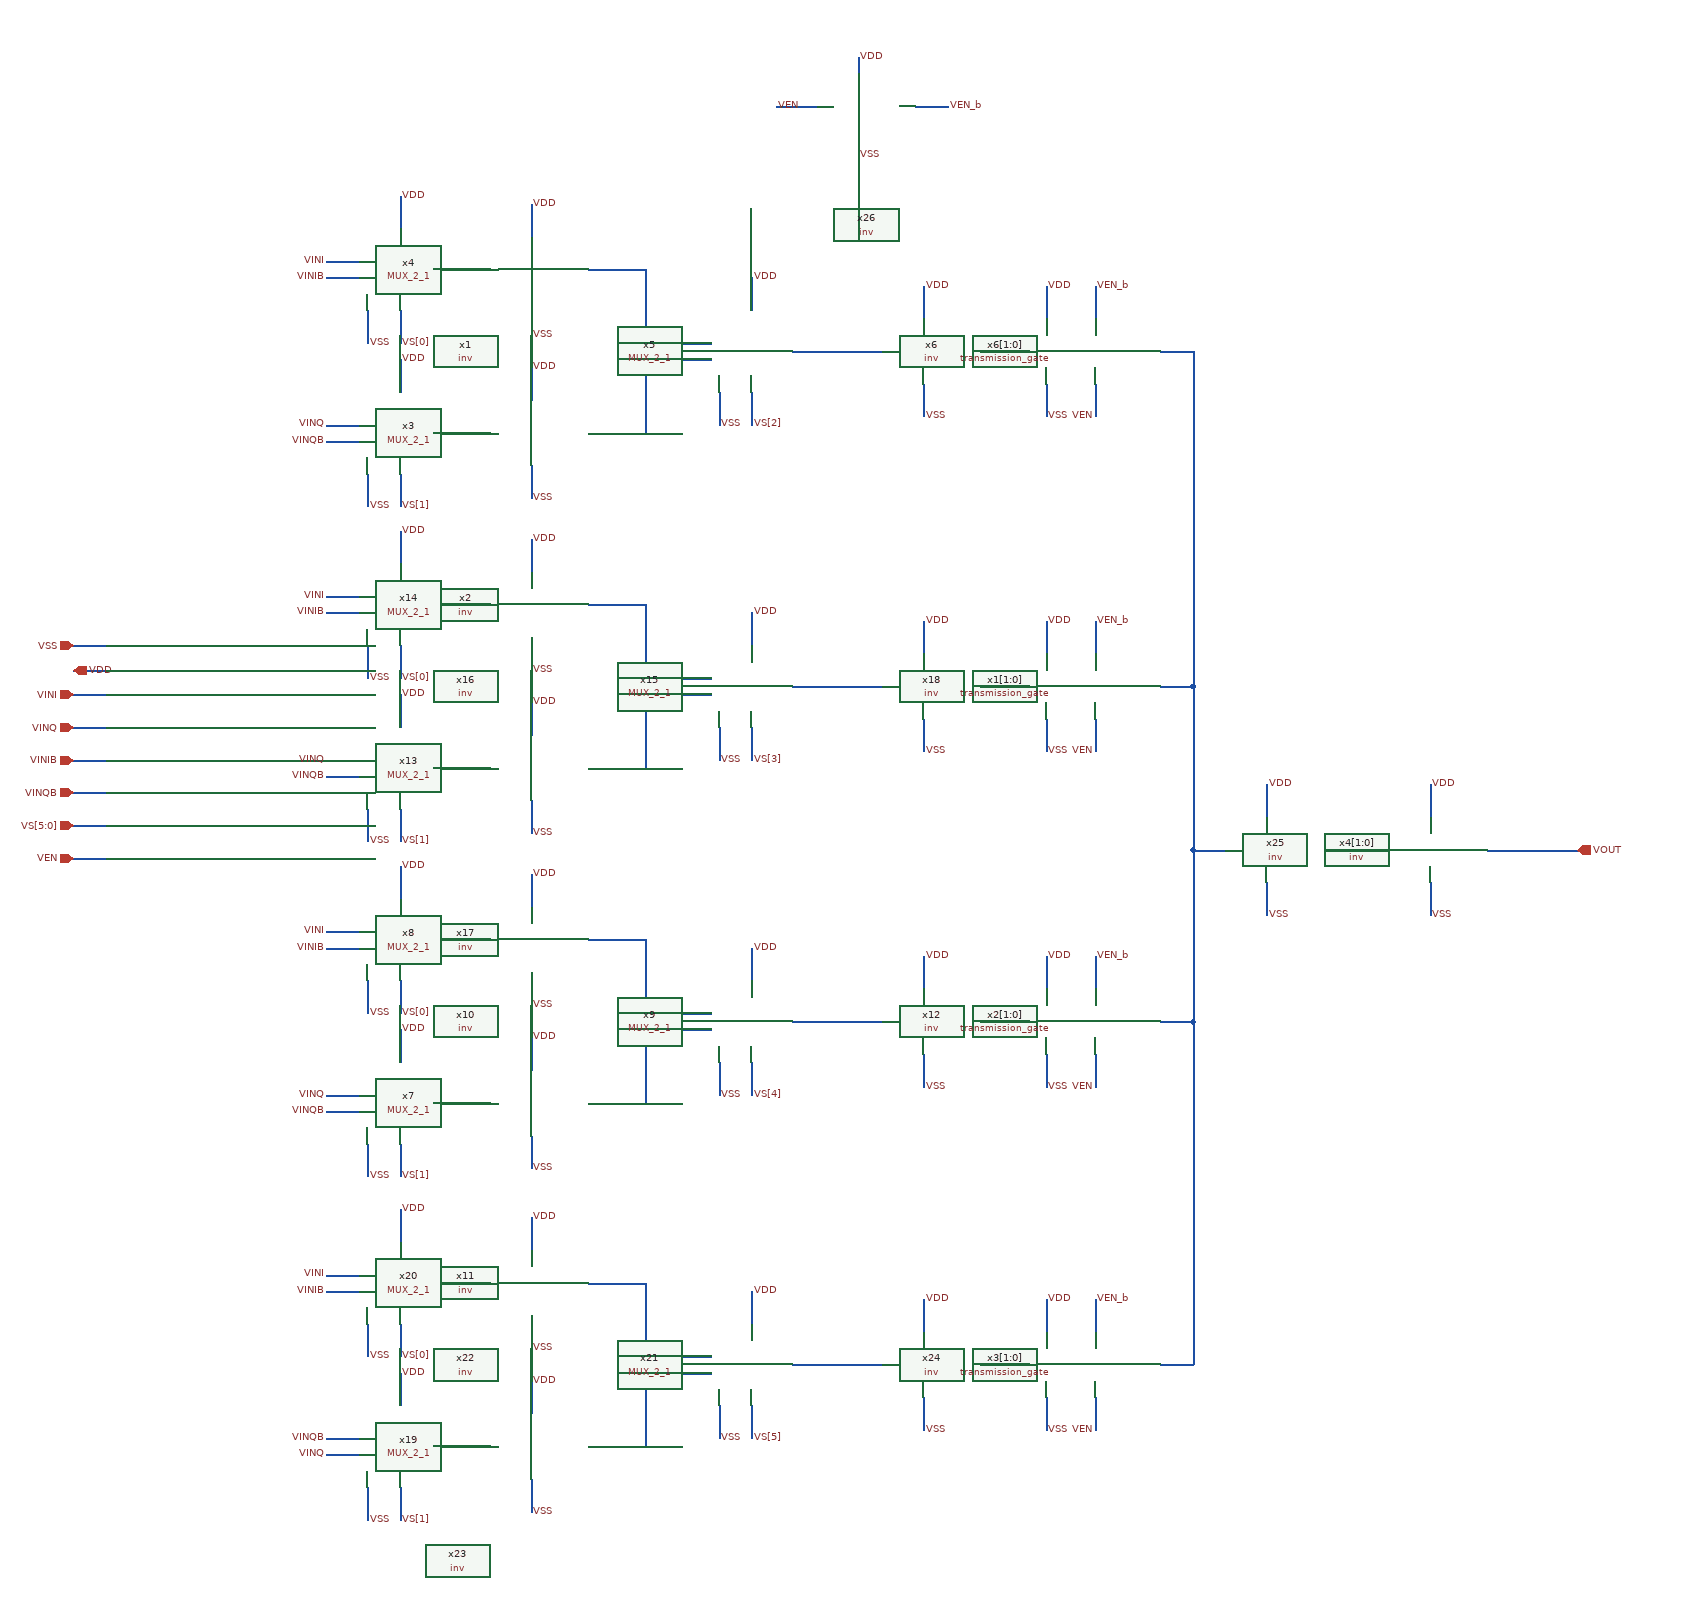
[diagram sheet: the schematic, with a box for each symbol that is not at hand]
v {xschem version=3.4.8RC file_version=1.3}
G {}
K {}
V {}
S {}
F {}
E {}
N -920 -490 -880 -490 {lab=VINI}
N -920 -470 -880 -470 {lab=VINIB}
N -920 -290 -880 -290 {lab=VINQ}
N -920 -270 -880 -270 {lab=VINQB}
N -830 -370 -830 -330 {lab=VDD}
N -870 -430 -870 -390 {lab=VSS}
N -870 -230 -870 -190 {lab=VSS}
N -830 -570 -830 -530 {lab=VDD}
N -830 -430 -830 -390 {lab=VS[0]}
N -830 -230 -830 -190 {lab=VS[1]}
N -440 -330 -440 -290 {lab=VSS}
N -400 -470 -400 -430 {lab=VDD}
N -400 -330 -400 -290 {lab=VS[2]}
N -780 -480 -720 -480 {lab=#net1}
N -780 -280 -720 -280 {lab=#net2}
N -350 -380 -240 -380 {lab=#net3}
N -530 -390 -450 -390 {lab=#net4}
N -530 -370 -450 -370 {lab=#net5}
N -530 -480 -530 -390 {lab=#net4}
N -600 -480 -530 -480 {lab=#net4}
N -530 -370 -530 -280 {lab=#net5}
N -600 -280 -530 -280 {lab=#net5}
N -670 -560 -670 -520 {lab=VDD}
N -190 -460 -190 -420 {lab=VDD}
N -670 -360 -670 -320 {lab=VDD}
N -670 -240 -670 -200 {lab=VSS}
N -670 -440 -670 -400 {lab=VSS}
N -190 -340 -190 -300 {lab=VSS}
N -920 -80 -880 -80 {lab=VINI}
N -920 -60 -880 -60 {lab=VINIB}
N -920 120 -880 120 {lab=VINQ}
N -920 140 -880 140 {lab=VINQB}
N -830 40 -830 80 {lab=VDD}
N -870 -20 -870 20 {lab=VSS}
N -870 180 -870 220 {lab=VSS}
N -830 -160 -830 -120 {lab=VDD}
N -830 -20 -830 20 {lab=VS[0]}
N -830 180 -830 220 {lab=VS[1]}
N -440 80 -440 120 {lab=VSS}
N -400 -60 -400 -20 {lab=VDD}
N -400 80 -400 120 {lab=VS[3]}
N -780 -70 -720 -70 {lab=#net6}
N -780 130 -720 130 {lab=#net7}
N -350 30 -240 30 {lab=#net8}
N -530 20 -450 20 {lab=#net9}
N -530 40 -450 40 {lab=#net10}
N -530 -70 -530 20 {lab=#net9}
N -600 -70 -530 -70 {lab=#net9}
N -530 40 -530 130 {lab=#net10}
N -600 130 -530 130 {lab=#net10}
N -670 -150 -670 -110 {lab=VDD}
N -670 50 -670 90 {lab=VDD}
N -670 170 -670 210 {lab=VSS}
N -670 -30 -670 10 {lab=VSS}
N -190 70 -190 110 {lab=VSS}
N -920 330 -880 330 {lab=VINI}
N -920 350 -880 350 {lab=VINIB}
N -920 530 -880 530 {lab=VINQ}
N -920 550 -880 550 {lab=VINQB}
N -830 450 -830 490 {lab=VDD}
N -870 390 -870 430 {lab=VSS}
N -870 590 -870 630 {lab=VSS}
N -830 250 -830 290 {lab=VDD}
N -830 390 -830 430 {lab=VS[0]}
N -830 590 -830 630 {lab=VS[1]}
N -400 350 -400 390 {lab=VDD}
N -400 490 -400 530 {lab=VS[4]}
N -780 340 -720 340 {lab=#net11}
N -780 540 -720 540 {lab=#net12}
N -350 440 -240 440 {lab=#net13}
N -530 430 -450 430 {lab=#net14}
N -530 450 -450 450 {lab=#net15}
N -530 340 -530 430 {lab=#net14}
N -600 340 -530 340 {lab=#net14}
N -530 450 -530 540 {lab=#net15}
N -600 540 -530 540 {lab=#net15}
N -670 260 -670 300 {lab=VDD}
N -190 360 -190 400 {lab=VDD}
N -670 460 -670 500 {lab=VDD}
N -670 580 -670 620 {lab=VSS}
N -670 380 -670 420 {lab=VSS}
N -190 480 -190 520 {lab=VSS}
N -920 750 -880 750 {lab=VINI}
N -920 770 -880 770 {lab=VINIB}
N -920 950 -880 950 {lab=VINQB}
N -920 970 -880 970 {lab=VINQ}
N -830 870 -830 910 {lab=VDD}
N -870 810 -870 850 {lab=VSS}
N -870 1010 -870 1050 {lab=VSS}
N -830 670 -830 710 {lab=VDD}
N -830 810 -830 850 {lab=VS[0]}
N -830 1010 -830 1050 {lab=VS[1]}
N -400 770 -400 810 {lab=VDD}
N -400 910 -400 950 {lab=VS[5]}
N -780 760 -720 760 {lab=#net16}
N -780 960 -720 960 {lab=#net17}
N -350 860 -240 860 {lab=#net18}
N -530 850 -450 850 {lab=#net19}
N -530 870 -450 870 {lab=#net20}
N -530 760 -530 850 {lab=#net19}
N -600 760 -530 760 {lab=#net19}
N -530 870 -530 960 {lab=#net20}
N -600 960 -530 960 {lab=#net20}
N -670 680 -670 720 {lab=VDD}
N -190 780 -190 820 {lab=VDD}
N -670 880 -670 920 {lab=VDD}
N -670 1000 -670 1040 {lab=VSS}
N -670 800 -670 840 {lab=VSS}
N -190 900 -190 940 {lab=VSS}
N 20 -340 20 -300 {lab=VEN}
N 20 -460 20 -420 {lab=VEN_b}
N -40 -460 -40 -420 {lab=VDD}
N -40 -340 -40 -300 {lab=VSS}
N 20 70 20 110 {lab=VEN}
N 20 -50 20 -10 {lab=VEN_b}
N -40 -50 -40 -10 {lab=VDD}
N -40 70 -40 110 {lab=VSS}
N 20 480 20 520 {lab=VEN}
N 20 360 20 400 {lab=VEN_b}
N -40 360 -40 400 {lab=VDD}
N -40 480 -40 520 {lab=VSS}
N 20 900 20 940 {lab=VEN}
N 20 780 20 820 {lab=VEN_b}
N -40 780 -40 820 {lab=VDD}
N -40 900 -40 940 {lab=VSS}
N 100 860 140 860 {lab=#net21}
N 140 440 140 860 {lab=#net21}
N 100 -380 140 -380 {lab=#net21}
N 100 30 140 30 {lab=#net21}
N 140 -380 140 30 {lab=#net21}
N 100 440 140 440 {lab=#net21}
N 140 230 140 440 {lab=#net21}
N 500 230 610 230 {lab=VOUT}
N 230 150 230 190 {lab=VDD}
N 230 270 230 310 {lab=VSS}
N 300 230 380 230 {lab=#net22}
N 430 150 430 190 {lab=VDD}
N 430 270 430 310 {lab=VSS}
N 140 230 180 230 {lab=#net21}
N 140 30 140 230 {lab=#net21}
N -120 860 -60 860 {lab=#net23}
N -120 440 -60 440 {lab=#net24}
N -120 30 -60 30 {lab=#net25}
N -120 -380 -60 -380 {lab=#net26}
N -270 -740 -270 -720 {lab=VDD}
N -270 -640 -270 -620 {lab=VSS}
N -200 -680 -160 -680 {lab=VEN_b}
N -1230 40 -1190 40 {lab=VINI}
N -1230 80 -1190 80 {lab=VINQ}
N -1230 120 -1190 120 {lab=VINIB}
N -1230 160 -1190 160 {lab=VINQB}
N -1230 240 -1190 240 {lab=VEN}
N -1230 200 -1190 200 {lab=VS[5:0]}
N -1230 -20 -1190 -20 {lab=VSS}
N -1230 10 -1190 10 {lab=VDD}
N -370 -680 -320 -680 {lab=VEN}
N -440 490 -440 530 {lab=VSS}
N -440 910 -440 950 {lab=VSS}
N -190 -50 -190 -10 {lab=VDD}
C {MUX_2_1.sym} -910 -200 0 0 {name=x3}
C {MUX_2_1.sym} -910 -400 0 0 {name=x4}
C {lab_wire.sym} -830 -370 2 0 {name=p12 sig_type=std_logic lab=VDD}
C {lab_wire.sym} -870 -390 2 0 {name=p13 sig_type=std_logic lab=VSS}
C {lab_wire.sym} -830 -390 2 0 {name=p17 sig_type=std_logic lab=VS[0]}
C {MUX_2_1.sym} -480 -300 0 0 {name=x5}
C {lab_wire.sym} -870 -190 2 0 {name=p20 sig_type=std_logic lab=VSS}
C {lab_wire.sym} -830 -570 2 0 {name=p21 sig_type=std_logic lab=VDD}
C {lab_wire.sym} -400 -290 2 0 {name=p22 sig_type=std_logic lab=VS[2]}
C {lab_wire.sym} -830 -190 2 0 {name=p18 sig_type=std_logic lab=VS[1]
}
C {iopin.sym} -1230 10 0 1 {name=p1 lab=VDD}
C {iopin.sym} -1230 -20 2 0 {name=p5 lab=VSS}
C {inv.sym} -760 -340 0 0 {name=x1}
C {inv.sym} -760 -140 0 0 {name=x2}
C {inv.sym} -280 -240 0 0 {name=x6}
C {lab_wire.sym} -670 -560 2 0 {name=p8 sig_type=std_logic lab=VDD}
C {lab_wire.sym} -190 -460 2 0 {name=p9 sig_type=std_logic lab=VDD}
C {lab_wire.sym} -670 -360 2 0 {name=p10 sig_type=std_logic lab=VDD}
C {lab_wire.sym} -670 -200 2 0 {name=p11 sig_type=std_logic lab=VSS}
C {lab_wire.sym} -670 -400 2 0 {name=p14 sig_type=std_logic lab=VSS}
C {lab_wire.sym} -190 -300 2 0 {name=p15 sig_type=std_logic lab=VSS}
C {MUX_2_1.sym} -910 210 0 0 {name=x13}
C {MUX_2_1.sym} -910 10 0 0 {name=x14}
C {lab_wire.sym} -830 40 2 0 {name=p41 sig_type=std_logic lab=VDD}
C {lab_wire.sym} -870 20 2 0 {name=p42 sig_type=std_logic lab=VSS}
C {lab_wire.sym} -830 20 2 0 {name=p43 sig_type=std_logic lab=VS[0]}
C {MUX_2_1.sym} -480 110 0 0 {name=x15}
C {lab_wire.sym} -870 220 2 0 {name=p44 sig_type=std_logic lab=VSS}
C {lab_wire.sym} -830 -160 2 0 {name=p45 sig_type=std_logic lab=VDD}
C {lab_wire.sym} -400 120 2 0 {name=p46 sig_type=std_logic lab=VS[3]}
C {lab_wire.sym} -830 220 2 0 {name=p47 sig_type=std_logic lab=VS[1]
}
C {inv.sym} -760 70 0 0 {name=x16}
C {inv.sym} -760 270 0 0 {name=x17}
C {inv.sym} -280 170 0 0 {name=x18}
C {lab_wire.sym} -670 -150 2 0 {name=p55 sig_type=std_logic lab=VDD}
C {lab_wire.sym} -670 50 2 0 {name=p57 sig_type=std_logic lab=VDD}
C {lab_wire.sym} -670 210 2 0 {name=p58 sig_type=std_logic lab=VSS}
C {lab_wire.sym} -670 10 2 0 {name=p59 sig_type=std_logic lab=VSS}
C {lab_wire.sym} -190 110 2 0 {name=p60 sig_type=std_logic lab=VSS}
C {MUX_2_1.sym} -910 620 0 0 {name=x7}
C {MUX_2_1.sym} -910 420 0 0 {name=x8}
C {lab_wire.sym} -830 450 2 0 {name=p2 sig_type=std_logic lab=VDD}
C {lab_wire.sym} -870 430 2 0 {name=p19 sig_type=std_logic lab=VSS}
C {lab_wire.sym} -830 430 2 0 {name=p23 sig_type=std_logic lab=VS[0]}
C {MUX_2_1.sym} -480 520 0 0 {name=x9}
C {lab_wire.sym} -870 630 2 0 {name=p24 sig_type=std_logic lab=VSS}
C {lab_wire.sym} -830 250 2 0 {name=p25 sig_type=std_logic lab=VDD}
C {lab_wire.sym} -400 530 2 0 {name=p26 sig_type=std_logic lab=VS[4]}
C {lab_wire.sym} -830 630 2 0 {name=p27 sig_type=std_logic lab=VS[1]}
C {inv.sym} -760 480 0 0 {name=x10}
C {inv.sym} -760 680 0 0 {name=x11}
C {inv.sym} -280 580 0 0 {name=x12}
C {lab_wire.sym} -670 260 2 0 {name=p35 sig_type=std_logic lab=VDD}
C {lab_wire.sym} -190 360 2 0 {name=p36 sig_type=std_logic lab=VDD}
C {lab_wire.sym} -670 460 2 0 {name=p37 sig_type=std_logic lab=VDD}
C {lab_wire.sym} -670 620 2 0 {name=p38 sig_type=std_logic lab=VSS}
C {lab_wire.sym} -670 420 2 0 {name=p39 sig_type=std_logic lab=VSS}
C {lab_wire.sym} -190 520 2 0 {name=p40 sig_type=std_logic lab=VSS}
C {MUX_2_1.sym} -910 1040 0 0 {name=x19}
C {MUX_2_1.sym} -910 840 0 0 {name=x20}
C {lab_wire.sym} -830 870 2 0 {name=p61 sig_type=std_logic lab=VDD}
C {lab_wire.sym} -870 850 2 0 {name=p62 sig_type=std_logic lab=VSS}
C {lab_wire.sym} -830 850 2 0 {name=p63 sig_type=std_logic lab=VS[0]}
C {MUX_2_1.sym} -480 940 0 0 {name=x21}
C {lab_wire.sym} -870 1050 2 0 {name=p64 sig_type=std_logic lab=VSS}
C {lab_wire.sym} -830 670 2 0 {name=p65 sig_type=std_logic lab=VDD}
C {lab_wire.sym} -400 950 2 0 {name=p66 sig_type=std_logic lab=VS[5]
}
C {lab_wire.sym} -830 1050 2 0 {name=p67 sig_type=std_logic lab=VS[1]}
C {inv.sym} -760 900 0 0 {name=x22}
C {inv.sym} -760 1100 0 0 {name=x23}
C {inv.sym} -280 1000 0 0 {name=x24}
C {lab_wire.sym} -670 680 2 0 {name=p75 sig_type=std_logic lab=VDD}
C {lab_wire.sym} -190 780 2 0 {name=p76 sig_type=std_logic lab=VDD}
C {lab_wire.sym} -670 880 2 0 {name=p77 sig_type=std_logic lab=VDD}
C {lab_wire.sym} -670 1040 2 0 {name=p78 sig_type=std_logic lab=VSS}
C {lab_wire.sym} -670 840 2 0 {name=p79 sig_type=std_logic lab=VSS}
C {lab_wire.sym} -190 940 2 0 {name=p80 sig_type=std_logic lab=VSS}
C {transmission_gate.sym} 20 -380 0 0 {name=x6[1:0]}
C {lab_wire.sym} 20 -300 0 0 {name=p16 sig_type=std_logic lab=VEN}
C {lab_wire.sym} 20 -460 2 0 {name=p34 sig_type=std_logic lab=VEN_b
}
C {lab_wire.sym} -40 -460 2 0 {name=p54 sig_type=std_logic lab=VDD}
C {lab_wire.sym} -40 -300 2 0 {name=p74 sig_type=std_logic lab=VSS}
C {transmission_gate.sym} 20 30 0 0 {name=x1[1:0]}
C {lab_wire.sym} 20 110 0 0 {name=p81 sig_type=std_logic lab=VEN}
C {lab_wire.sym} 20 -50 2 0 {name=p82 sig_type=std_logic lab=VEN_b
}
C {lab_wire.sym} -40 -50 2 0 {name=p83 sig_type=std_logic lab=VDD}
C {lab_wire.sym} -40 110 2 0 {name=p84 sig_type=std_logic lab=VSS}
C {transmission_gate.sym} 20 440 0 0 {name=x2[1:0]}
C {lab_wire.sym} 20 520 0 0 {name=p85 sig_type=std_logic lab=VEN}
C {lab_wire.sym} 20 360 2 0 {name=p86 sig_type=std_logic lab=VEN_b
}
C {lab_wire.sym} -40 360 2 0 {name=p87 sig_type=std_logic lab=VDD}
C {lab_wire.sym} -40 520 2 0 {name=p88 sig_type=std_logic lab=VSS}
C {transmission_gate.sym} 20 860 0 0 {name=x3[1:0]}
C {lab_wire.sym} 20 940 0 0 {name=p89 sig_type=std_logic lab=VEN}
C {lab_wire.sym} 20 780 2 0 {name=p90 sig_type=std_logic lab=VEN_b
}
C {lab_wire.sym} -40 780 2 0 {name=p91 sig_type=std_logic lab=VDD}
C {lab_wire.sym} -40 940 2 0 {name=p92 sig_type=std_logic lab=VSS}
C {opin.sym} 610 230 0 0 {name=p93 lab=VOUT}
C {inv.sym} 140 370 0 0 {name=x25}
C {lab_wire.sym} 230 310 2 0 {name=p94 sig_type=std_logic lab=VSS}
C {lab_wire.sym} 230 150 2 0 {name=p95 sig_type=std_logic lab=VDD}
C {inv.sym} 340 370 0 0 {name=x4[1:0]}
C {lab_wire.sym} 430 310 2 0 {name=p96 sig_type=std_logic lab=VSS}
C {lab_wire.sym} 430 150 2 0 {name=p97 sig_type=std_logic lab=VDD}
C {inv.sym} -360 -540 0 0 {name=x26
}
C {lab_wire.sym} -270 -740 2 0 {name=p98 sig_type=std_logic lab=VDD}
C {lab_wire.sym} -270 -620 2 0 {name=p99 sig_type=std_logic lab=VSS
}
C {lab_wire.sym} -160 -680 2 0 {name=p101 sig_type=std_logic lab=VEN_b
}
C {ipin.sym} -1230 200 0 0 {name=p102 lab=VS[5:0]}
C {ipin.sym} -1230 40 0 0 {name=p103 lab=VINI}
C {ipin.sym} -1230 80 0 0 {name=p104 lab=VINQ}
C {ipin.sym} -1230 120 0 0 {name=p106 lab=VINIB}
C {ipin.sym} -1230 160 0 0 {name=p107 lab=VINQB}
C {ipin.sym} -1230 240 0 0 {name=p108 lab=VEN}
C {lab_wire.sym} -400 -470 2 0 {name=p109 sig_type=std_logic lab=VDD}
C {lab_wire.sym} -440 -290 2 0 {name=p110 sig_type=std_logic lab=VSS}
C {lab_wire.sym} -400 -60 2 0 {name=p48 sig_type=std_logic lab=VDD}
C {lab_wire.sym} -440 120 2 0 {name=p49 sig_type=std_logic lab=VSS
}
C {lab_wire.sym} -370 -680 2 0 {name=p111 sig_type=std_logic lab=VEN}
C {lab_wire.sym} -920 -490 0 0 {name=p3 sig_type=std_logic lab=VINI}
C {lab_wire.sym} -920 -470 0 0 {name=p105 sig_type=std_logic lab=VINIB}
C {lab_wire.sym} -920 -80 0 0 {name=p50 sig_type=std_logic lab=VINI}
C {lab_wire.sym} -920 -60 0 0 {name=p51 sig_type=std_logic lab=VINIB}
C {lab_wire.sym} -920 330 0 0 {name=p30 sig_type=std_logic lab=VINI}
C {lab_wire.sym} -920 350 0 0 {name=p31 sig_type=std_logic lab=VINIB}
C {lab_wire.sym} -920 750 0 0 {name=p70 sig_type=std_logic lab=VINI}
C {lab_wire.sym} -920 770 0 0 {name=p71 sig_type=std_logic lab=VINIB}
C {lab_wire.sym} -920 120 0 0 {name=p52 sig_type=std_logic lab=VINQ}
C {lab_wire.sym} -920 140 0 0 {name=p53 sig_type=std_logic lab=VINQB}
C {lab_wire.sym} -920 530 0 0 {name=p32 sig_type=std_logic lab=VINQ
}
C {lab_wire.sym} -920 550 0 0 {name=p33 sig_type=std_logic lab=VINQB}
C {lab_wire.sym} -920 950 0 0 {name=p72 sig_type=std_logic lab=VINQB}
C {lab_wire.sym} -920 970 0 0 {name=p73 sig_type=std_logic lab=VINQ}
C {lab_wire.sym} -920 -290 0 0 {name=p6 sig_type=std_logic lab=VINQ}
C {lab_wire.sym} -920 -270 0 0 {name=p7 sig_type=std_logic lab=VINQB}
C {lab_wire.sym} -400 350 2 0 {name=p28 sig_type=std_logic lab=VDD}
C {lab_wire.sym} -440 530 2 0 {name=p29 sig_type=std_logic lab=VSS
}
C {lab_wire.sym} -440 950 2 0 {name=p69 sig_type=std_logic lab=VSS
}
C {lab_wire.sym} -400 770 2 0 {name=p68 sig_type=std_logic lab=VDD}
C {lab_wire.sym} -190 -50 2 0 {name=p4 sig_type=std_logic lab=VDD}
